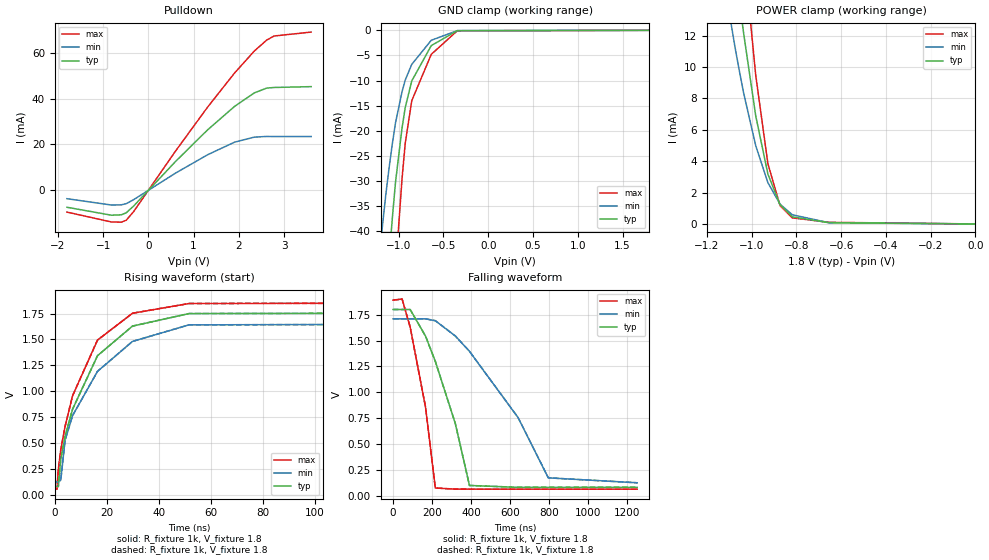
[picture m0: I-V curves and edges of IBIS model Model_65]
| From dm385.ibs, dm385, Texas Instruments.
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| Model based on original model for BI2C1833DVFZP18_SSDHH
|   Sub model BI2C1833_NORAML_5P_1P8
[model]   Model_65
|[Description]  [1.8V-I/O_OPEN_DRAIN-NORMAL-I2C STANDARD, IND, 5%]
|   I2C STANDARD,NORMAL,Industrial temperature range (-40C to 125C,
|   25C nominal),5% power supply tolerance
|[Input Load]   NORMAL
|[Output Drive] I2C STANDARD
|Voltage   1.8V
|Mode   I/O_OPEN_DRAIN
Model_type   I/O_open_drain
Polarity   Non-Inverting
Enable   Active-Low
Vinl =  0.54
Vinh =  1.26
Cref =  400pF
Rref =  528
Vref =  1.8V
Vmeas =  0.9
C_comp   2.858406p   2.734081p   3.127023p
[Model Spec]
Vinl   0.54   0.513   0.567
Vinh   1.26   1.197   1.323
[Temperature Range]   25   125   -40
[Voltage Range]   1.8   1.71   1.89
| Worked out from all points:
|   slope of the pulldown table from 0 to 0.27 V, typ, clamps not added: 47.3 ohm
|   GND clamp passes 1 mA (typ) near -0.51 V on its own axis
|   POWER clamp passes 1 mA (typ) near -0.86 V on its own axis
|   rising waveform, R_fixture 1k, V_fixture 1.8: 20-80 % time 17.4ns typ, 21ns min, 15.1ns max; typ from 0.08 V to 1.8 V
|   rising waveform, R_fixture 1k, V_fixture 1.8: 20-80 % time 17.4ns typ, 21ns min, 15.1ns max; typ from 0.08 V to 1.8 V
|   falling waveform, R_fixture 1k, V_fixture 1.8: 20-80 % time 166ns typ, 334ns min, 96.1ns max; typ from 1.8 V to 0.081 V
|   falling waveform, R_fixture 1k, V_fixture 1.8: 20-80 % time 166ns typ, 334ns min, 96.1ns max; typ from 1.8 V to 0.081 V
[POWER_clamp]
-1.8V     125.6mA    90.89mA    174.1mA
-1.127V   23.23mA    15.78mA    33.46mA
-1.073V   16.42mA    11.17mA    23.65mA
-1.055V   14.31mA    9.773mA    20.55mA
-1.036V   12.19mA    8.373mA    17.45mA
-1.018V   10.43mA    7.247mA    14.8mA
-981.8mV  6.903mA    4.997mA    9.497mA
-927.3mV  3.179mA    2.633mA    3.84mA
-872.7mV  1.209mA    1.257mA    1.153mA
-818.2mV  452.5uA    585.6uA    387.6uA
-654.5mV  79.53uA    79.22uA    104.5uA
0V        23.06nA    161nA      231.7nA
[Pulldown]
-1.8V     -7.503mA   -3.749mA   -9.614mA
-818.2mV  -10.98mA   -6.525mA   -13.94mA
-600mV    -10.81mA   -6.446mA   -14.04mA
-490.9mV  -9.941mA   -5.925mA   -13.2mA
-327.3mV  -6.99mA    -4.193mA   -9.444mA
600mV     12.53mA    7.452mA    17.08mA
1.309V    26.38mA    15.49mA    36.33mA
1.909V    36.72mA    21.03mA    51.36mA
2.345V    42.61mA    23.22mA    60.96mA
2.618V    44.7mA     23.51mA    65.74mA
2.782V    44.96mA    23.46mA    67.52mA
3.6V      45.33mA    23.47mA    69.22mA
[GND_clamp]
-1.8V     -251.3mA   -159.1mA   -395.2mA
-1.255V   -84.32mA   -51.1mA    -135.4mA
-1.145V   -54.62mA   -32.82mA   -87.84mA
-1.109V   -45.84mA   -27.58mA   -73.48mA
-1.073V   -37.72mA   -22.78mA   -60.15mA
-1.036V   -30.26mA   -18.42mA   -47.83mA
-963.6mV  -19.52mA   -12.26mA   -29.65mA
-927.3mV  -15.37mA   -9.897mA   -22.49mA
-854.5mV  -10.08mA   -6.778mA   -14.01mA
-636.4mV  -3.04mA    -1.976mA   -4.778mA
-345.5mV  -61.12uA   -62.1uA    -91.05uA
1.8V      23.06nA    175.4nA    217.6nA
[Ramp]
dV/dt_f  1.0421373/0.1690776u 0.95636594/0.33698972u  1.1137593/98.456538n
dV/dt_r   71.5998m/0.85131504n 65.265563m/1.6966724n 69.079016m/0.59616743n
R_load = 1k
[Rising Waveform]
R_fixture = 1k
V_fixture = 1.8
V_fixture_min = 1.71
V_fixture_max = 1.89
0s        80mV       123.9mV    62.24mV
844.7ps   80mV       123.9mV    54.5mV
1.364ns   80mV       123.9mV    243.8mV
2.298ns   344.9mV    141.3mV    432.7mV
3.95ns    562.2mV    526.4mV    658.5mV
6.833ns   825.8mV    764mV      955.1mV
16.43ns   1.343V     1.192V     1.494V
29.89ns   1.629V     1.481V     1.753V
51.66ns   1.75V      1.641V     1.847V
1.25us    1.8V       1.71V      1.89V
[Rising Waveform]
R_fixture = 1k
V_fixture = 1.8
V_fixture_min = 1.71
V_fixture_max = 1.89
0s        80mV       123.9mV    62.24mV
844.7ps   80mV       123.9mV    54.5mV
1.364ns   80mV       123.9mV    243.8mV
2.298ns   344.9mV    141.3mV    432.7mV
3.95ns    562.2mV    526.4mV    658.5mV
6.833ns   825.8mV    764mV      955.1mV
16.43ns   1.343V     1.192V     1.494V
29.89ns   1.629V     1.481V     1.753V
51.66ns   1.75V      1.641V     1.847V
1.25us    1.8V       1.71V      1.89V
[Falling Waveform]
R_fixture = 1k
V_fixture = 1.8
V_fixture_min = 1.71
V_fixture_max = 1.89
0s        1.8V       1.71V      1.891V
46.45ns   1.8V       1.71V      1.901V
87.78ns   1.8V       1.71V      1.63V
166.6ns   1.542V     1.71V      854.3mV
216.5ns   1.299V     1.692V     74.63mV
319ns     697mV      1.544V     63.42mV
391.3ns   99.06mV    1.396V     63.23mV
640.1ns   80.76mV    755.8mV    63.16mV
795ns     80.68mV    172.6mV    63.16mV
1.25us    80.67mV    124.9mV    63.16mV
[Falling Waveform]
R_fixture = 1k
V_fixture = 1.8
V_fixture_min = 1.71
V_fixture_max = 1.89
0s        1.8V       1.71V      1.891V
46.45ns   1.8V       1.71V      1.901V
87.78ns   1.8V       1.71V      1.63V
166.6ns   1.542V     1.71V      854.3mV
216.5ns   1.299V     1.692V     74.63mV
319ns     697mV      1.544V     63.42mV
391.3ns   99.06mV    1.396V     63.23mV
640.1ns   80.76mV    755.8mV    63.16mV
795ns     80.68mV    172.6mV    63.16mV
1.25us    80.67mV    124.9mV    63.16mV
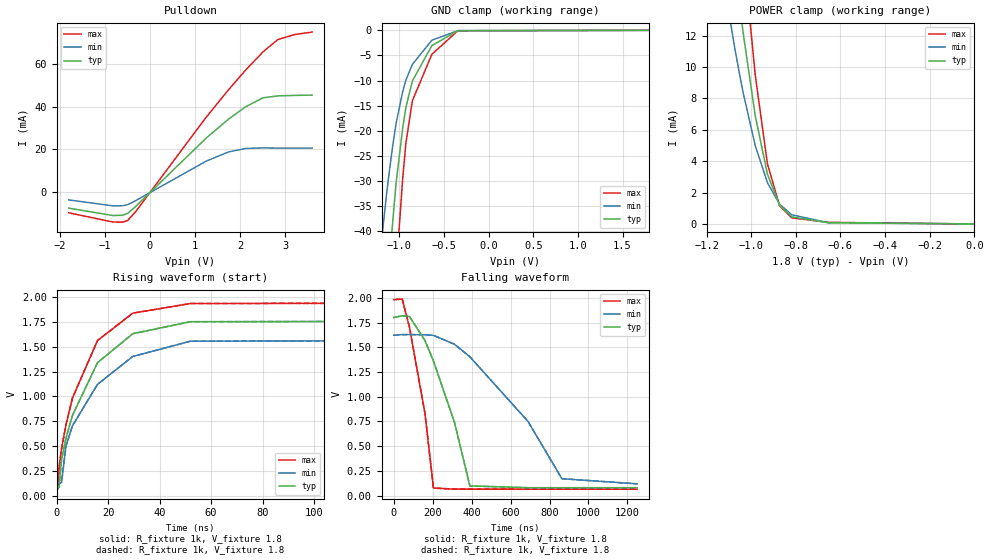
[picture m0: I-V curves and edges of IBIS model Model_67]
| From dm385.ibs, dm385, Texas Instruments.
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| Model based on original model for BI2C1833DVFZP18_SSDHH
|   Sub model BI2C1833_NORAML_10P_1P8
[model]   Model_67
|[Description]  [1.8V-I/O_OPEN_DRAIN-NORMAL-I2C STANDARD, IND, 10%]
|   I2C STANDARD,NORMAL,Industrial temperature range (-40C to 125C,
|   25C nominal),10% power supply tolerance
|[Input Load]   NORMAL
|[Output Drive] I2C STANDARD
|Voltage   1.8V
|Mode   I/O_OPEN_DRAIN
Model_type   I/O_open_drain
Polarity   Non-Inverting
Enable   Active-Low
Vinl =  0.54
Vinh =  1.26
Cref =  400pF
Rref =  528
Vref =  1.8V
Vmeas =  0.9
C_comp   2.858406p   2.529817p   3.16381p
[Model Spec]
Vinl   0.54   0.486   0.594
Vinh   1.26   1.134   1.386
[Temperature Range]   25   125   -40
[Voltage Range]   1.8   1.62   1.98
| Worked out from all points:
|   slope of the pulldown table from 0 to 0.27 V, typ, clamps not added: 47.3 ohm
|   GND clamp passes 1 mA (typ) near -0.51 V on its own axis
|   POWER clamp passes 1 mA (typ) near -0.86 V on its own axis
|   rising waveform, R_fixture 1k, V_fixture 1.8: 20-80 % time 17.4ns typ, 21ns min, 15.1ns max; typ from 0.08 V to 1.8 V
|   rising waveform, R_fixture 1k, V_fixture 1.8: 20-80 % time 17.4ns typ, 21ns min, 15.1ns max; typ from 0.08 V to 1.8 V
|   falling waveform, R_fixture 1k, V_fixture 1.8: 20-80 % time 167ns typ, 358ns min, 92.4ns max; typ from 1.8 V to 0.081 V
|   falling waveform, R_fixture 1k, V_fixture 1.8: 20-80 % time 167ns typ, 358ns min, 92.4ns max; typ from 1.8 V to 0.081 V
[POWER_clamp]
-1.8V     125.6mA    90.89mA    174.1mA
-1.127V   23.23mA    15.78mA    33.46mA
-1.073V   16.42mA    11.17mA    23.65mA
-1.055V   14.31mA    9.772mA    20.55mA
-1.036V   12.19mA    8.372mA    17.45mA
-1.018V   10.43mA    7.246mA    14.8mA
-981.8mV  6.903mA    4.996mA    9.497mA
-927.3mV  3.179mA    2.632mA    3.84mA
-872.7mV  1.209mA    1.257mA    1.153mA
-818.2mV  452.5uA    585uA      387.7uA
-654.5mV  79.53uA    79.04uA    104.6uA
0V        23.06nA    140.3nA    354.4nA
[Pulldown]
-1.8V     -7.503mA   -3.655mA   -9.689mA
-818.2mV  -10.98mA   -6.45mA    -14mA
-600mV    -10.81mA   -6.386mA   -14.08mA
-490.9mV  -9.941mA   -5.873mA   -13.24mA
-327.3mV  -6.99mA    -4.156mA   -9.47mA
1.255V    25.37mA    14.53mA    35.12mA
1.745V    34.08mA    18.77mA    47.85mA
2.127V    39.93mA    20.4mA     57.12mA
2.509V    44.07mA    20.67mA    65.52mA
2.836V    44.97mA    20.56mA    71.29mA
3.218V    45.2mA     20.56mA    73.69mA
3.6V      45.33mA    20.57mA    74.8mA
[GND_clamp]
-1.8V     -251.3mA   -159.1mA   -395.2mA
-1.255V   -84.32mA   -51.1mA    -135.4mA
-1.145V   -54.62mA   -32.82mA   -87.84mA
-1.109V   -45.84mA   -27.58mA   -73.48mA
-1.073V   -37.72mA   -22.78mA   -60.15mA
-1.036V   -30.26mA   -18.42mA   -47.83mA
-963.6mV  -19.52mA   -12.26mA   -29.65mA
-927.3mV  -15.37mA   -9.897mA   -22.49mA
-854.5mV  -10.08mA   -6.778mA   -14.01mA
-636.4mV  -3.04mA    -1.976mA   -4.779mA
-345.5mV  -61.12uA   -61.97uA   -91.06uA
1.8V      23.06nA    171.3nA    312.3nA
[Ramp]
dV/dt_f  1.0421385/0.16906483u 0.90494077/0.36005027u  1.1678122/94.773502n
dV/dt_r 71.604308m/0.85098861n 62.323663m/1.7221033n 70.734353m/0.6449258n
R_load = 1k
[Rising Waveform]
R_fixture = 1k
V_fixture = 1.8
V_fixture_min = 1.62
V_fixture_max = 1.98
0s        79.89mV    118.4mV    66.28mV
428.7ps   79.89mV    118.4mV    66.28mV
958.7ps   84.73mV    118.4mV    275.1mV
1.959ns   363.7mV    135.1mV    475.9mV
3.654ns   577.5mV    498.4mV    712.5mV
6.175ns   808.5mV    703.6mV    983.7mV
15.93ns   1.34V      1.122V     1.563V
29.61ns   1.631V     1.402V     1.838V
52.01ns   1.752V     1.556V     1.935V
1.25us    1.8V       1.62V      1.98V
[Rising Waveform]
R_fixture = 1k
V_fixture = 1.8
V_fixture_min = 1.62
V_fixture_max = 1.98
0s        79.89mV    118.4mV    66.28mV
428.7ps   79.89mV    118.4mV    66.28mV
958.7ps   84.73mV    118.4mV    275.1mV
1.959ns   363.7mV    135.1mV    475.9mV
3.654ns   577.5mV    498.4mV    712.5mV
6.175ns   808.5mV    703.6mV    983.7mV
15.93ns   1.34V      1.122V     1.563V
29.61ns   1.631V     1.402V     1.838V
52.01ns   1.752V     1.556V     1.935V
1.25us    1.8V       1.62V      1.98V
[Falling Waveform]
R_fixture = 1k
V_fixture = 1.8
V_fixture_min = 1.62
V_fixture_max = 1.98
0s        1.801V     1.621V     1.981V
43.5ns    1.818V     1.628V     1.987V
80.76ns   1.811V     1.628V     1.704V
160.7ns   1.567V     1.626V     828.5mV
204.1ns   1.36V      1.62V      77.1mV
311.7ns   743.4mV    1.531V     66.21mV
390.9ns   98.95mV    1.404V     66.04mV
689.6ns   80.72mV    750mV      65.97mV
863.6ns   80.68mV    171.3mV    65.97mV
1.25us    80.67mV    119.8mV    65.97mV
[Falling Waveform]
R_fixture = 1k
V_fixture = 1.8
V_fixture_min = 1.62
V_fixture_max = 1.98
0s        1.801V     1.621V     1.981V
43.5ns    1.818V     1.628V     1.987V
80.76ns   1.811V     1.628V     1.704V
160.7ns   1.567V     1.626V     828.5mV
204.1ns   1.36V      1.62V      77.1mV
311.7ns   743.4mV    1.531V     66.21mV
390.9ns   98.95mV    1.404V     66.04mV
689.6ns   80.72mV    750mV      65.97mV
863.6ns   80.68mV    171.3mV    65.97mV
1.25us    80.67mV    119.8mV    65.97mV
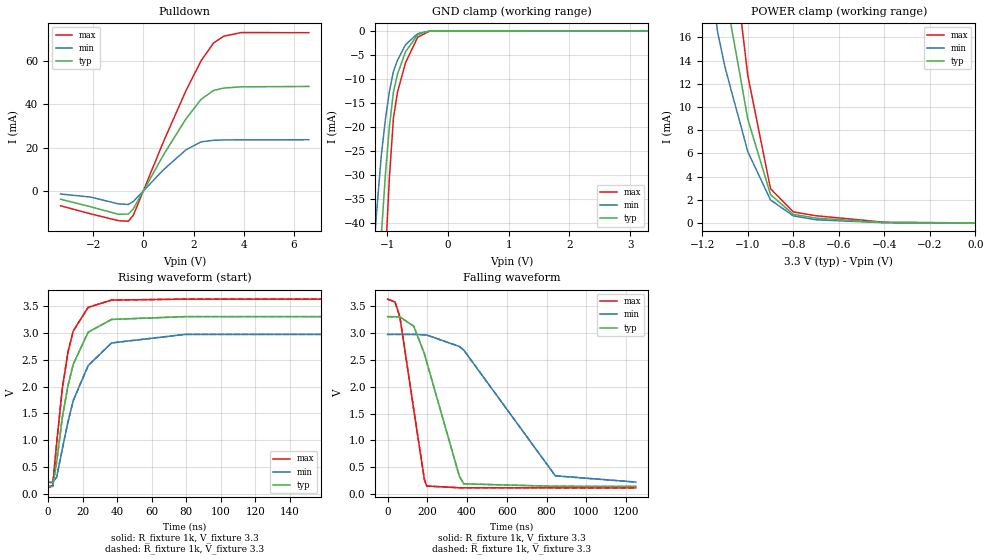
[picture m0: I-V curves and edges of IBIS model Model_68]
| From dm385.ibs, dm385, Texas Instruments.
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| Model based on original model for BI2C1833DVFZP18_SSDHH
|   Sub model BI2C1833_NORAML_10P_3P3
[model]   Model_68
|[Description]  [3.3V-I/O_OPEN_DRAIN-NORMAL-I2C STANDARD, IND, 10%]
|   I2C STANDARD,NORMAL,Industrial temperature range (-40C to 125C,
|   25C nominal),10% power supply tolerance
|[Input Load]   NORMAL
|[Output Drive] I2C STANDARD
|Voltage   3.3V
|Mode   I/O_OPEN_DRAIN
Model_type   I/O_open_drain
Polarity   Non-Inverting
Enable   Active-Low
Vinl =  0.99
Vinh =  2.31
Cref =  400pF
Rref =  528
Vref =  1.8V
Vmeas =  1.65
C_comp   3.826936p   2.767369p   5.268171p
[Model Spec]
Vinl   0.99   0.891   1.089
Vinh   2.31   2.079   2.541
[Temperature Range]   25   125   -40
[Voltage Range]   3.3   2.97   3.63
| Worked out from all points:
|   slope of the pulldown table from 0 to 0.495 V, typ, clamps not added: 47.7 ohm
|   GND clamp passes 1 mA (typ) near -0.51 V on its own axis
|   POWER clamp passes 1 mA (typ) near -0.81 V on its own axis
|   rising waveform, R_fixture 1k, V_fixture 3.3: 20-80 % time 11.5ns typ, 16ns min, 8.93ns max; typ from 0.148 V to 3.29 V
|   rising waveform, R_fixture 1k, V_fixture 3.3: 20-80 % time 11.5ns typ, 16ns min, 8.93ns max; typ from 0.148 V to 3.29 V
|   falling waveform, R_fixture 1k, V_fixture 3.3: 20-80 % time 149ns typ, 315ns min, 85.8ns max; typ from 3.29 V to 0.148 V
|   falling waveform, R_fixture 1k, V_fixture 3.3: 20-80 % time 149ns typ, 315ns min, 85.8ns max; typ from 3.29 V to 0.148 V
[POWER_clamp]
-3.3V     371.9mA    370.7mA    506.1mA
-1.133V   24.49mA    16.53mA    35.37mA
-1.1V     20.05mA    13.45mA    29.08mA
-1.067V   16.35mA    11.02mA    23.63mA
-1.033V   12.66mA    8.589mA    18.19mA
-1V       8.957mA    6.157mA    12.75mA
-900mV    2.454mA    1.995mA    2.958mA
-800mV    749.9uA    620.3uA    962.7uA
-700mV    426.8uA    282.9uA    630.6uA
-400mV    48.77uA    29.05uA    73.94uA
0V        4.596uA    2.036uA    9.305uA
[Pulldown]
-3.3V     -3.962mA   -1.526mA   -6.996mA
-2.1V     -7.46mA    -2.966mA   -10.74mA
-1V       -10.91mA   -6.109mA   -13.87mA
-600mV    -10.84mA   -6.367mA   -14.18mA
-400mV    -8.439mA   -5.006mA   -11.41mA
800mV     16.55mA    9.687mA    22.68mA
1.7V      33.31mA    18.95mA    46.4mA
2.3V      42.31mA    22.63mA    60.18mA
2.8V      46.45mA    23.36mA    68.46mA
3.2V      47.54mA    23.51mA    71.56mA
3.9V      48.12mA    23.53mA    73.26mA
6.6V      48.3mA     23.61mA    73.21mA
[GND_clamp]
-3.3V     -732.9mA   -579.5mA   -1.135A
-1.233V   -77.75mA   -47.44mA   -124.9mA
-1.167V   -59.87mA   -36.39mA   -96.3mA
-1.1V     -42.93mA   -26.1mA    -68.88mA
-1.033V   -30.16mA   -18.6mA    -47.71mA
-966.7mV  -20.1mA    -12.73mA   -30.84mA
-900mV    -12.77mA   -8.484mA   -18.26mA
-833.3mV  -9.047mA   -6.154mA   -12.83mA
-700mV    -4.35mA    -2.882mA   -6.627mA
-500mV    -792.1uA   -572.8uA   -1.328mA
-300mV    -20.03uA   -28.11uA   -28.26uA
3.3V      4.596uA    11.21uA    5.613uA
[Ramp]
dV/dt_f  1.8954887/0.1492067u  1.6524661/0.31643332u  2.1103219/86.143627n
dV/dt_r 85.087907m/13.236053n  77.98547m/6.4033251n 80.131523m/8.972681n
R_load = 1k
[Rising Waveform]
R_fixture = 1k
V_fixture = 3.3
V_fixture_min = 2.97
V_fixture_max = 3.63
0s        148.1mV    220.5mV    120.2mV
2.643ns   148.1mV    220.5mV    164.3mV
4.909ns   592mV      319.4mV    942.1mV
8.168ns   1.419V     836.1mV    1.954V
11.44ns   2.011V     1.337V     2.635V
14.54ns   2.414V     1.74V      3.031V
23.16ns   3.008V     2.388V     3.469V
36.72ns   3.245V     2.809V     3.604V
79.13ns   3.297V     2.967V     3.622V
1.25us    3.295V     2.968V     3.621V
[Rising Waveform]
R_fixture = 1k
V_fixture = 3.3
V_fixture_min = 2.97
V_fixture_max = 3.63
0s        148.1mV    220.5mV    120.2mV
2.643ns   148.1mV    220.5mV    164.3mV
4.909ns   592mV      319.4mV    942.1mV
8.168ns   1.419V     836.1mV    1.954V
11.44ns   2.011V     1.337V     2.635V
14.54ns   2.414V     1.74V      3.031V
23.16ns   3.008V     2.388V     3.469V
36.72ns   3.245V     2.809V     3.604V
79.13ns   3.297V     2.967V     3.622V
1.25us    3.295V     2.968V     3.621V
[Falling Waveform]
R_fixture = 1k
V_fixture = 3.3
V_fixture_min = 2.97
V_fixture_max = 3.63
0s        3.295V     2.967V     3.621V
37.3ns    3.295V     2.967V     3.569V
62.07ns   3.29V      2.967V     3.287V
131.5ns   3.119V     2.966V     1.575V
185.2ns   2.609V     2.959V     272.9mV
196.8ns   2.454V     2.956V     155mV
361ns     339.1mV    2.743V     122.6mV
383.3ns   195.8mV    2.676V     122.4mV
844ns     149.5mV    344.8mV    121.2mV
1.25us    148.5mV    227.9mV    121.1mV
[Falling Waveform]
R_fixture = 1k
V_fixture = 3.3
V_fixture_min = 2.97
V_fixture_max = 3.63
0s        3.295V     2.967V     3.621V
37.3ns    3.295V     2.967V     3.569V
62.07ns   3.29V      2.967V     3.287V
131.5ns   3.119V     2.966V     1.575V
185.2ns   2.609V     2.959V     272.9mV
196.8ns   2.454V     2.956V     155mV
361ns     339.1mV    2.743V     122.6mV
383.3ns   195.8mV    2.676V     122.4mV
844ns     149.5mV    344.8mV    121.2mV
1.25us    148.5mV    227.9mV    121.1mV
